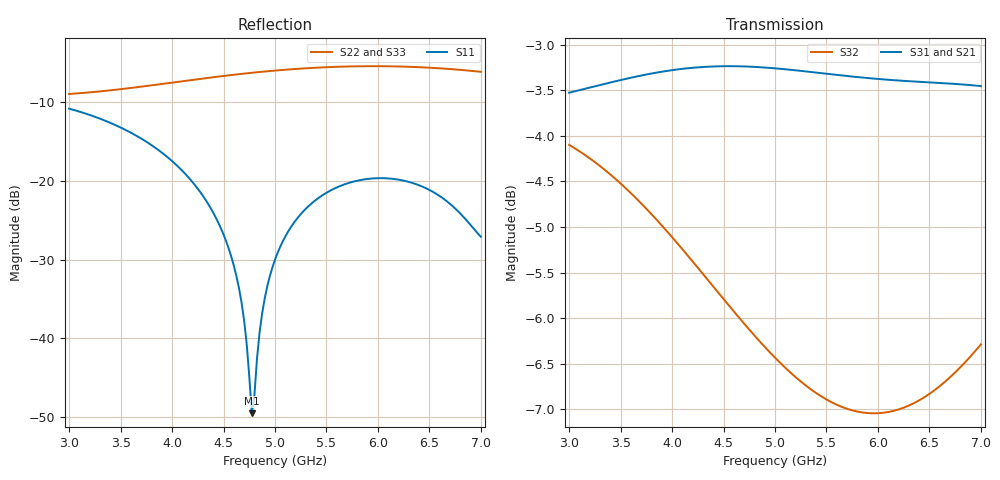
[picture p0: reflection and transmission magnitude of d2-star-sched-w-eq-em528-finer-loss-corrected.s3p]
! yapnr Order 0 prediction d2-star-sched-w-eq-em528-finer: predictions/D2/variants/d2-star-sched-w-eq-em528/finer.s3p, loss-corrected
! substrate W-eq-em528; coupon model OSHPARK-4L-EM528; correction: ratio (port line)
! |S21|, |S31| (and S12, S13) scaled, phases kept; 50 ohm, e^(+jwt)
# GHz S RI R 50
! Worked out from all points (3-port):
!   161 points, 3 GHz to 7 GHz, reference 50 ohm
!   strongest paths, dB at 3 GHz, 4 GHz, 5 GHz, 6 GHz, 7 GHz:
!     S31: -3.5, -3.3, -3.3, -3.4, -3.5
!     S21: -3.5, -3.3, -3.3, -3.4, -3.5
!     S32: -4.1, -5.1, -6.4, -7.0, -6.3
!   lowest |S11| = -49.6 dB at 4.775 GHz (marker M1), VSWR 1.01, Z = 49.9 + j0.304 ohm
!   |S11| at or under -10 dB: start of sweep to end of sweep
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3  -0.1059 0.2679  -0.3904 -0.5403  -0.3904 -0.5403
   -0.3903 -0.5398  0.3161 0.1662  -0.6049 -0.1519
   -0.3903 -0.5398  -0.6049 -0.1519  0.3161 0.1662
4.35  0.0361 0.0617  -0.6819 0.0908  -0.6819 0.0908
      -0.6826 0.0897  0.2423 -0.3817  -0.2639 0.4547
      -0.6826 0.0897  -0.2639 0.4547  0.2423 -0.3817
4.65  0.0125 0.0167  -0.6388 0.255  -0.6388 0.255
      -0.6403 0.2539  0.1343 -0.458  -0.1317 0.4839
      -0.6403 0.2539  -0.1317 0.4839  0.1343 -0.458
4.775  -0.00133 0.00305  -0.6085 0.3191  -0.6085 0.3191
       -0.6104 0.3183  0.0839 -0.4798  -0.0789 0.4858
       -0.6104 0.3183  -0.0789 0.4858  0.0839 -0.4798
4.875  -0.0133 -0.00536  -0.5796 0.3679  -0.5796 0.3679
       -0.5817 0.3672  0.042 -0.4927  -0.0381 0.4835
       -0.5817 0.3672  -0.0381 0.4835  0.042 -0.4927
5  -0.0289 -0.0127  -0.5377 0.4249  -0.5377 0.4249
   -0.5401 0.4245  -0.0116 -0.503  0.0106 0.4767
   -0.5401 0.4245  0.0106 0.4767  -0.0116 -0.503
5.35  -0.0698 -0.0152  -0.3925 0.5571  -0.3925 0.5571
      -0.3953 0.558  -0.1619 -0.4969  0.133 0.4383
      -0.3953 0.558  0.133 0.4383  -0.1619 -0.4969
5.9  -0.1017 0.0158  -0.1086 0.6666  -0.1086 0.6666
     -0.1102 0.6696  -0.3655 -0.3927  0.2868 0.3397
     -0.1102 0.6696  0.2868 0.3397  -0.3655 -0.3927
6.5  -0.0776 0.0406  0.2222 0.6337  0.2222 0.6337
     0.2238 0.6367  -0.4892 -0.1901  0.4137 0.1905
     0.2238 0.6367  0.4137 0.1905  -0.4892 -0.1901
7  -0.043 0.00977  0.4634 0.4824  0.4634 0.4824
   0.4669 0.4829  -0.494 -0.00505  0.4843 0.023
   0.4669 0.4829  0.4843 0.023  -0.494 -0.00505
